VERSION 5.8 ;
BUSBITCHARS "[]" ;
DIVIDERCHAR "/" ;
UNITS
    DATABASE MICRONS 1000 ;
END UNITS

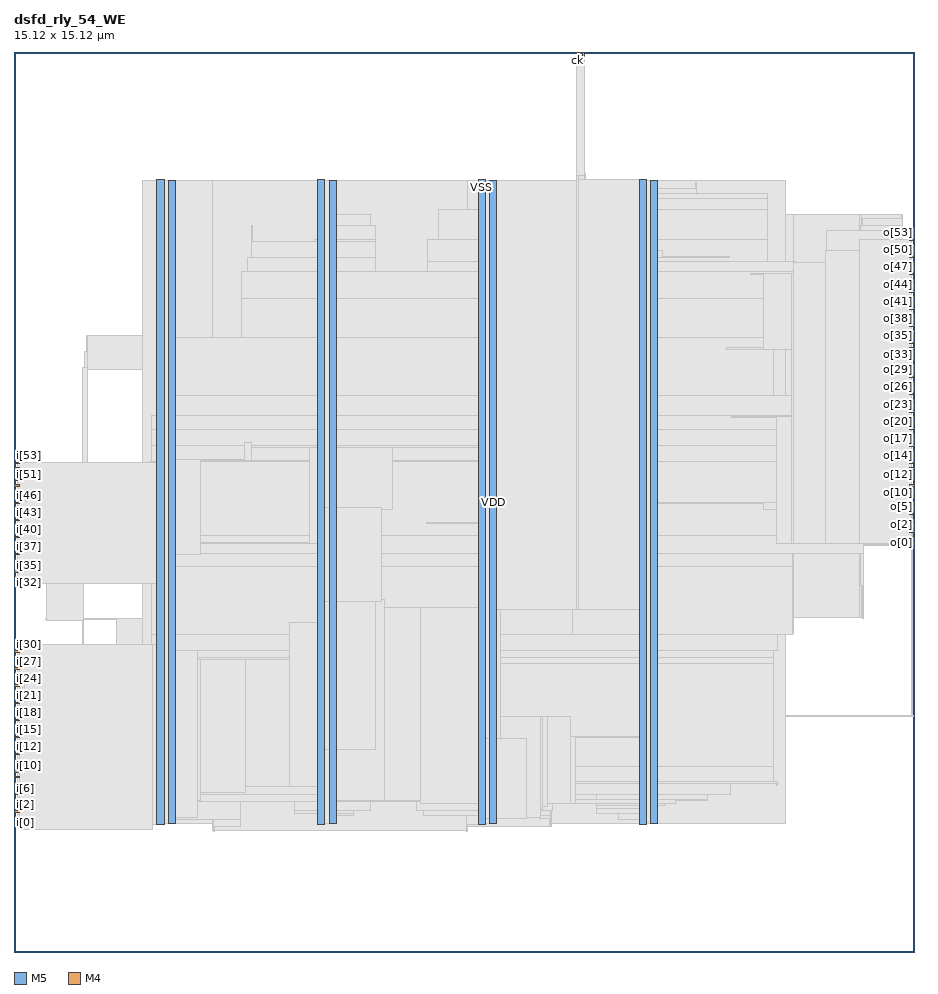
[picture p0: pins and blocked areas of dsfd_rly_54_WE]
MACRO dsfd_rly_54_WE
  FOREIGN dsfd_rly_54_WE 0 0 ;
  CLASS BLOCK ;
  SIZE 15.12 BY 15.12 ;
  PIN ck
    DIRECTION INPUT ;
    USE SIGNAL ;
    PORT
      LAYER M5 ;
        RECT  9.456 15.036 9.48 15.12 ;
    END
  END ck
  PIN i[0]
    DIRECTION INPUT ;
    USE SIGNAL ;
    PORT
      LAYER M4 ;
        RECT  0 2.16 0.084 2.184 ;
    END
  END i[0]
  PIN i[10]
    DIRECTION INPUT ;
    USE SIGNAL ;
    PORT
      LAYER M4 ;
        RECT  0 3.12 0.084 3.144 ;
    END
  END i[10]
  PIN i[11]
    DIRECTION INPUT ;
    USE SIGNAL ;
    PORT
      LAYER M4 ;
        RECT  0 3.216 0.084 3.24 ;
    END
  END i[11]
  PIN i[12]
    DIRECTION INPUT ;
    USE SIGNAL ;
    PORT
      LAYER M4 ;
        RECT  0 3.312 0.084 3.336 ;
    END
  END i[12]
  PIN i[13]
    DIRECTION INPUT ;
    USE SIGNAL ;
    PORT
      LAYER M4 ;
        RECT  0 3.408 0.084 3.432 ;
    END
  END i[13]
  PIN i[14]
    DIRECTION INPUT ;
    USE SIGNAL ;
    PORT
      LAYER M4 ;
        RECT  0 3.504 0.084 3.528 ;
    END
  END i[14]
  PIN i[15]
    DIRECTION INPUT ;
    USE SIGNAL ;
    PORT
      LAYER M4 ;
        RECT  0 3.6 0.084 3.624 ;
    END
  END i[15]
  PIN i[16]
    DIRECTION INPUT ;
    USE SIGNAL ;
    PORT
      LAYER M4 ;
        RECT  0 3.696 0.084 3.72 ;
    END
  END i[16]
  PIN i[17]
    DIRECTION INPUT ;
    USE SIGNAL ;
    PORT
      LAYER M4 ;
        RECT  0 3.792 0.084 3.816 ;
    END
  END i[17]
  PIN i[18]
    DIRECTION INPUT ;
    USE SIGNAL ;
    PORT
      LAYER M4 ;
        RECT  0 3.888 0.084 3.912 ;
    END
  END i[18]
  PIN i[19]
    DIRECTION INPUT ;
    USE SIGNAL ;
    PORT
      LAYER M4 ;
        RECT  0 3.984 0.084 4.008 ;
    END
  END i[19]
  PIN i[1]
    DIRECTION INPUT ;
    USE SIGNAL ;
    PORT
      LAYER M4 ;
        RECT  0 2.256 0.084 2.28 ;
    END
  END i[1]
  PIN i[20]
    DIRECTION INPUT ;
    USE SIGNAL ;
    PORT
      LAYER M4 ;
        RECT  0 4.08 0.084 4.104 ;
    END
  END i[20]
  PIN i[21]
    DIRECTION INPUT ;
    USE SIGNAL ;
    PORT
      LAYER M4 ;
        RECT  0 4.176 0.084 4.2 ;
    END
  END i[21]
  PIN i[22]
    DIRECTION INPUT ;
    USE SIGNAL ;
    PORT
      LAYER M4 ;
        RECT  0 4.272 0.084 4.296 ;
    END
  END i[22]
  PIN i[23]
    DIRECTION INPUT ;
    USE SIGNAL ;
    PORT
      LAYER M4 ;
        RECT  0 4.368 0.084 4.392 ;
    END
  END i[23]
  PIN i[24]
    DIRECTION INPUT ;
    USE SIGNAL ;
    PORT
      LAYER M4 ;
        RECT  0 4.464 0.084 4.488 ;
    END
  END i[24]
  PIN i[25]
    DIRECTION INPUT ;
    USE SIGNAL ;
    PORT
      LAYER M4 ;
        RECT  0 4.56 0.084 4.584 ;
    END
  END i[25]
  PIN i[26]
    DIRECTION INPUT ;
    USE SIGNAL ;
    PORT
      LAYER M4 ;
        RECT  0 4.656 0.084 4.68 ;
    END
  END i[26]
  PIN i[27]
    DIRECTION INPUT ;
    USE SIGNAL ;
    PORT
      LAYER M4 ;
        RECT  0 4.752 0.084 4.776 ;
    END
  END i[27]
  PIN i[28]
    DIRECTION INPUT ;
    USE SIGNAL ;
    PORT
      LAYER M4 ;
        RECT  0 4.848 0.084 4.872 ;
    END
  END i[28]
  PIN i[29]
    DIRECTION INPUT ;
    USE SIGNAL ;
    PORT
      LAYER M4 ;
        RECT  0 4.944 0.084 4.968 ;
    END
  END i[29]
  PIN i[2]
    DIRECTION INPUT ;
    USE SIGNAL ;
    PORT
      LAYER M4 ;
        RECT  0 2.352 0.084 2.376 ;
    END
  END i[2]
  PIN i[30]
    DIRECTION INPUT ;
    USE SIGNAL ;
    PORT
      LAYER M4 ;
        RECT  0 5.04 0.084 5.064 ;
    END
  END i[30]
  PIN i[31]
    DIRECTION INPUT ;
    USE SIGNAL ;
    PORT
      LAYER M4 ;
        RECT  0 5.136 0.084 5.16 ;
    END
  END i[31]
  PIN i[32]
    DIRECTION INPUT ;
    USE SIGNAL ;
    PORT
      LAYER M4 ;
        RECT  0 6.192 0.084 6.216 ;
    END
  END i[32]
  PIN i[33]
    DIRECTION INPUT ;
    USE SIGNAL ;
    PORT
      LAYER M4 ;
        RECT  0 6.288 0.084 6.312 ;
    END
  END i[33]
  PIN i[34]
    DIRECTION INPUT ;
    USE SIGNAL ;
    PORT
      LAYER M4 ;
        RECT  0 6.384 0.084 6.408 ;
    END
  END i[34]
  PIN i[35]
    DIRECTION INPUT ;
    USE SIGNAL ;
    PORT
      LAYER M4 ;
        RECT  0 6.48 0.084 6.504 ;
    END
  END i[35]
  PIN i[36]
    DIRECTION INPUT ;
    USE SIGNAL ;
    PORT
      LAYER M4 ;
        RECT  0 6.576 0.084 6.6 ;
    END
  END i[36]
  PIN i[37]
    DIRECTION INPUT ;
    USE SIGNAL ;
    PORT
      LAYER M4 ;
        RECT  0 6.672 0.084 6.696 ;
    END
  END i[37]
  PIN i[38]
    DIRECTION INPUT ;
    USE SIGNAL ;
    PORT
      LAYER M4 ;
        RECT  0 6.768 0.084 6.792 ;
    END
  END i[38]
  PIN i[39]
    DIRECTION INPUT ;
    USE SIGNAL ;
    PORT
      LAYER M4 ;
        RECT  0 6.864 0.084 6.888 ;
    END
  END i[39]
  PIN i[3]
    DIRECTION INPUT ;
    USE SIGNAL ;
    PORT
      LAYER M4 ;
        RECT  0 2.448 0.084 2.472 ;
    END
  END i[3]
  PIN i[40]
    DIRECTION INPUT ;
    USE SIGNAL ;
    PORT
      LAYER M4 ;
        RECT  0 6.96 0.084 6.984 ;
    END
  END i[40]
  PIN i[41]
    DIRECTION INPUT ;
    USE SIGNAL ;
    PORT
      LAYER M4 ;
        RECT  0 7.056 0.084 7.08 ;
    END
  END i[41]
  PIN i[42]
    DIRECTION INPUT ;
    USE SIGNAL ;
    PORT
      LAYER M4 ;
        RECT  0 7.152 0.084 7.176 ;
    END
  END i[42]
  PIN i[43]
    DIRECTION INPUT ;
    USE SIGNAL ;
    PORT
      LAYER M4 ;
        RECT  0 7.248 0.084 7.272 ;
    END
  END i[43]
  PIN i[44]
    DIRECTION INPUT ;
    USE SIGNAL ;
    PORT
      LAYER M4 ;
        RECT  0 7.344 0.084 7.368 ;
    END
  END i[44]
  PIN i[45]
    DIRECTION INPUT ;
    USE SIGNAL ;
    PORT
      LAYER M4 ;
        RECT  0 7.44 0.084 7.464 ;
    END
  END i[45]
  PIN i[46]
    DIRECTION INPUT ;
    USE SIGNAL ;
    PORT
      LAYER M4 ;
        RECT  0 7.536 0.084 7.56 ;
    END
  END i[46]
  PIN i[47]
    DIRECTION INPUT ;
    USE SIGNAL ;
    PORT
      LAYER M4 ;
        RECT  0 7.632 0.084 7.656 ;
    END
  END i[47]
  PIN i[48]
    DIRECTION INPUT ;
    USE SIGNAL ;
    PORT
      LAYER M4 ;
        RECT  0 7.728 0.084 7.752 ;
    END
  END i[48]
  PIN i[49]
    DIRECTION INPUT ;
    USE SIGNAL ;
    PORT
      LAYER M4 ;
        RECT  0 7.824 0.084 7.848 ;
    END
  END i[49]
  PIN i[4]
    DIRECTION INPUT ;
    USE SIGNAL ;
    PORT
      LAYER M4 ;
        RECT  0 2.544 0.084 2.568 ;
    END
  END i[4]
  PIN i[50]
    DIRECTION INPUT ;
    USE SIGNAL ;
    PORT
      LAYER M4 ;
        RECT  0 7.92 0.084 7.944 ;
    END
  END i[50]
  PIN i[51]
    DIRECTION INPUT ;
    USE SIGNAL ;
    PORT
      LAYER M4 ;
        RECT  0 8.016 0.084 8.04 ;
    END
  END i[51]
  PIN i[52]
    DIRECTION INPUT ;
    USE SIGNAL ;
    PORT
      LAYER M4 ;
        RECT  0 8.112 0.084 8.136 ;
    END
  END i[52]
  PIN i[53]
    DIRECTION INPUT ;
    USE SIGNAL ;
    PORT
      LAYER M4 ;
        RECT  0 8.208 0.084 8.232 ;
    END
  END i[53]
  PIN i[5]
    DIRECTION INPUT ;
    USE SIGNAL ;
    PORT
      LAYER M4 ;
        RECT  0 2.64 0.084 2.664 ;
    END
  END i[5]
  PIN i[6]
    DIRECTION INPUT ;
    USE SIGNAL ;
    PORT
      LAYER M4 ;
        RECT  0 2.736 0.084 2.76 ;
    END
  END i[6]
  PIN i[7]
    DIRECTION INPUT ;
    USE SIGNAL ;
    PORT
      LAYER M4 ;
        RECT  0 2.832 0.084 2.856 ;
    END
  END i[7]
  PIN i[8]
    DIRECTION INPUT ;
    USE SIGNAL ;
    PORT
      LAYER M4 ;
        RECT  0 2.928 0.084 2.952 ;
    END
  END i[8]
  PIN i[9]
    DIRECTION INPUT ;
    USE SIGNAL ;
    PORT
      LAYER M4 ;
        RECT  0 3.024 0.084 3.048 ;
    END
  END i[9]
  PIN o[0]
    DIRECTION OUTPUT ;
    USE SIGNAL ;
    PORT
      LAYER M4 ;
        RECT  15.036 6.864 15.12 6.888 ;
    END
  END o[0]
  PIN o[10]
    DIRECTION OUTPUT ;
    USE SIGNAL ;
    PORT
      LAYER M4 ;
        RECT  15.036 7.824 15.12 7.848 ;
    END
  END o[10]
  PIN o[11]
    DIRECTION OUTPUT ;
    USE SIGNAL ;
    PORT
      LAYER M4 ;
        RECT  15.036 7.92 15.12 7.944 ;
    END
  END o[11]
  PIN o[12]
    DIRECTION OUTPUT ;
    USE SIGNAL ;
    PORT
      LAYER M4 ;
        RECT  15.036 8.016 15.12 8.04 ;
    END
  END o[12]
  PIN o[13]
    DIRECTION OUTPUT ;
    USE SIGNAL ;
    PORT
      LAYER M4 ;
        RECT  15.036 8.112 15.12 8.136 ;
    END
  END o[13]
  PIN o[14]
    DIRECTION OUTPUT ;
    USE SIGNAL ;
    PORT
      LAYER M4 ;
        RECT  15.036 8.208 15.12 8.232 ;
    END
  END o[14]
  PIN o[15]
    DIRECTION OUTPUT ;
    USE SIGNAL ;
    PORT
      LAYER M4 ;
        RECT  15.036 8.304 15.12 8.328 ;
    END
  END o[15]
  PIN o[16]
    DIRECTION OUTPUT ;
    USE SIGNAL ;
    PORT
      LAYER M4 ;
        RECT  15.036 8.4 15.12 8.424 ;
    END
  END o[16]
  PIN o[17]
    DIRECTION OUTPUT ;
    USE SIGNAL ;
    PORT
      LAYER M4 ;
        RECT  15.036 8.496 15.12 8.52 ;
    END
  END o[17]
  PIN o[18]
    DIRECTION OUTPUT ;
    USE SIGNAL ;
    PORT
      LAYER M4 ;
        RECT  15.036 8.592 15.12 8.616 ;
    END
  END o[18]
  PIN o[19]
    DIRECTION OUTPUT ;
    USE SIGNAL ;
    PORT
      LAYER M4 ;
        RECT  15.036 8.688 15.12 8.712 ;
    END
  END o[19]
  PIN o[1]
    DIRECTION OUTPUT ;
    USE SIGNAL ;
    PORT
      LAYER M4 ;
        RECT  15.036 6.96 15.12 6.984 ;
    END
  END o[1]
  PIN o[20]
    DIRECTION OUTPUT ;
    USE SIGNAL ;
    PORT
      LAYER M4 ;
        RECT  15.036 8.784 15.12 8.808 ;
    END
  END o[20]
  PIN o[21]
    DIRECTION OUTPUT ;
    USE SIGNAL ;
    PORT
      LAYER M4 ;
        RECT  15.036 8.88 15.12 8.904 ;
    END
  END o[21]
  PIN o[22]
    DIRECTION OUTPUT ;
    USE SIGNAL ;
    PORT
      LAYER M4 ;
        RECT  15.036 8.976 15.12 9 ;
    END
  END o[22]
  PIN o[23]
    DIRECTION OUTPUT ;
    USE SIGNAL ;
    PORT
      LAYER M4 ;
        RECT  15.036 9.072 15.12 9.096 ;
    END
  END o[23]
  PIN o[24]
    DIRECTION OUTPUT ;
    USE SIGNAL ;
    PORT
      LAYER M4 ;
        RECT  15.036 9.168 15.12 9.192 ;
    END
  END o[24]
  PIN o[25]
    DIRECTION OUTPUT ;
    USE SIGNAL ;
    PORT
      LAYER M4 ;
        RECT  15.036 9.264 15.12 9.288 ;
    END
  END o[25]
  PIN o[26]
    DIRECTION OUTPUT ;
    USE SIGNAL ;
    PORT
      LAYER M4 ;
        RECT  15.036 9.36 15.12 9.384 ;
    END
  END o[26]
  PIN o[27]
    DIRECTION OUTPUT ;
    USE SIGNAL ;
    PORT
      LAYER M4 ;
        RECT  15.036 9.456 15.12 9.48 ;
    END
  END o[27]
  PIN o[28]
    DIRECTION OUTPUT ;
    USE SIGNAL ;
    PORT
      LAYER M4 ;
        RECT  15.036 9.552 15.12 9.576 ;
    END
  END o[28]
  PIN o[29]
    DIRECTION OUTPUT ;
    USE SIGNAL ;
    PORT
      LAYER M4 ;
        RECT  15.036 9.648 15.12 9.672 ;
    END
  END o[29]
  PIN o[2]
    DIRECTION OUTPUT ;
    USE SIGNAL ;
    PORT
      LAYER M4 ;
        RECT  15.036 7.056 15.12 7.08 ;
    END
  END o[2]
  PIN o[30]
    DIRECTION OUTPUT ;
    USE SIGNAL ;
    PORT
      LAYER M4 ;
        RECT  15.036 9.744 15.12 9.768 ;
    END
  END o[30]
  PIN o[31]
    DIRECTION OUTPUT ;
    USE SIGNAL ;
    PORT
      LAYER M4 ;
        RECT  15.036 9.84 15.12 9.864 ;
    END
  END o[31]
  PIN o[32]
    DIRECTION OUTPUT ;
    USE SIGNAL ;
    PORT
      LAYER M4 ;
        RECT  15.036 9.936 15.12 9.96 ;
    END
  END o[32]
  PIN o[33]
    DIRECTION OUTPUT ;
    USE SIGNAL ;
    PORT
      LAYER M4 ;
        RECT  15.036 10.032 15.12 10.056 ;
    END
  END o[33]
  PIN o[34]
    DIRECTION OUTPUT ;
    USE SIGNAL ;
    PORT
      LAYER M4 ;
        RECT  15.036 10.128 15.12 10.152 ;
    END
  END o[34]
  PIN o[35]
    DIRECTION OUTPUT ;
    USE SIGNAL ;
    PORT
      LAYER M4 ;
        RECT  15.036 10.224 15.12 10.248 ;
    END
  END o[35]
  PIN o[36]
    DIRECTION OUTPUT ;
    USE SIGNAL ;
    PORT
      LAYER M4 ;
        RECT  15.036 10.32 15.12 10.344 ;
    END
  END o[36]
  PIN o[37]
    DIRECTION OUTPUT ;
    USE SIGNAL ;
    PORT
      LAYER M4 ;
        RECT  15.036 10.416 15.12 10.44 ;
    END
  END o[37]
  PIN o[38]
    DIRECTION OUTPUT ;
    USE SIGNAL ;
    PORT
      LAYER M4 ;
        RECT  15.036 10.512 15.12 10.536 ;
    END
  END o[38]
  PIN o[39]
    DIRECTION OUTPUT ;
    USE SIGNAL ;
    PORT
      LAYER M4 ;
        RECT  15.036 10.608 15.12 10.632 ;
    END
  END o[39]
  PIN o[3]
    DIRECTION OUTPUT ;
    USE SIGNAL ;
    PORT
      LAYER M4 ;
        RECT  15.036 7.152 15.12 7.176 ;
    END
  END o[3]
  PIN o[40]
    DIRECTION OUTPUT ;
    USE SIGNAL ;
    PORT
      LAYER M4 ;
        RECT  15.036 10.704 15.12 10.728 ;
    END
  END o[40]
  PIN o[41]
    DIRECTION OUTPUT ;
    USE SIGNAL ;
    PORT
      LAYER M4 ;
        RECT  15.036 10.8 15.12 10.824 ;
    END
  END o[41]
  PIN o[42]
    DIRECTION OUTPUT ;
    USE SIGNAL ;
    PORT
      LAYER M4 ;
        RECT  15.036 10.896 15.12 10.92 ;
    END
  END o[42]
  PIN o[43]
    DIRECTION OUTPUT ;
    USE SIGNAL ;
    PORT
      LAYER M4 ;
        RECT  15.036 10.992 15.12 11.016 ;
    END
  END o[43]
  PIN o[44]
    DIRECTION OUTPUT ;
    USE SIGNAL ;
    PORT
      LAYER M4 ;
        RECT  15.036 11.088 15.12 11.112 ;
    END
  END o[44]
  PIN o[45]
    DIRECTION OUTPUT ;
    USE SIGNAL ;
    PORT
      LAYER M4 ;
        RECT  15.036 11.184 15.12 11.208 ;
    END
  END o[45]
  PIN o[46]
    DIRECTION OUTPUT ;
    USE SIGNAL ;
    PORT
      LAYER M4 ;
        RECT  15.036 11.28 15.12 11.304 ;
    END
  END o[46]
  PIN o[47]
    DIRECTION OUTPUT ;
    USE SIGNAL ;
    PORT
      LAYER M4 ;
        RECT  15.036 11.376 15.12 11.4 ;
    END
  END o[47]
  PIN o[48]
    DIRECTION OUTPUT ;
    USE SIGNAL ;
    PORT
      LAYER M4 ;
        RECT  15.036 11.472 15.12 11.496 ;
    END
  END o[48]
  PIN o[49]
    DIRECTION OUTPUT ;
    USE SIGNAL ;
    PORT
      LAYER M4 ;
        RECT  15.036 11.568 15.12 11.592 ;
    END
  END o[49]
  PIN o[4]
    DIRECTION OUTPUT ;
    USE SIGNAL ;
    PORT
      LAYER M4 ;
        RECT  15.036 7.248 15.12 7.272 ;
    END
  END o[4]
  PIN o[50]
    DIRECTION OUTPUT ;
    USE SIGNAL ;
    PORT
      LAYER M4 ;
        RECT  15.036 11.664 15.12 11.688 ;
    END
  END o[50]
  PIN o[51]
    DIRECTION OUTPUT ;
    USE SIGNAL ;
    PORT
      LAYER M4 ;
        RECT  15.036 11.76 15.12 11.784 ;
    END
  END o[51]
  PIN o[52]
    DIRECTION OUTPUT ;
    USE SIGNAL ;
    PORT
      LAYER M4 ;
        RECT  15.036 11.856 15.12 11.88 ;
    END
  END o[52]
  PIN o[53]
    DIRECTION OUTPUT ;
    USE SIGNAL ;
    PORT
      LAYER M4 ;
        RECT  15.036 11.952 15.12 11.976 ;
    END
  END o[53]
  PIN o[5]
    DIRECTION OUTPUT ;
    USE SIGNAL ;
    PORT
      LAYER M4 ;
        RECT  15.036 7.344 15.12 7.368 ;
    END
  END o[5]
  PIN o[6]
    DIRECTION OUTPUT ;
    USE SIGNAL ;
    PORT
      LAYER M4 ;
        RECT  15.036 7.44 15.12 7.464 ;
    END
  END o[6]
  PIN o[7]
    DIRECTION OUTPUT ;
    USE SIGNAL ;
    PORT
      LAYER M4 ;
        RECT  15.036 7.536 15.12 7.56 ;
    END
  END o[7]
  PIN o[8]
    DIRECTION OUTPUT ;
    USE SIGNAL ;
    PORT
      LAYER M4 ;
        RECT  15.036 7.632 15.12 7.656 ;
    END
  END o[8]
  PIN o[9]
    DIRECTION OUTPUT ;
    USE SIGNAL ;
    PORT
      LAYER M4 ;
        RECT  15.036 7.728 15.12 7.752 ;
    END
  END o[9]
  PIN rs
    DIRECTION INPUT ;
    USE SIGNAL ;
    PORT
      LAYER M5 ;
        RECT  9.552 15.036 9.576 15.12 ;
    END
  END rs
  PIN VDD
    DIRECTION INOUT ;
    USE POWER ;
    PORT
      LAYER M5 ;
        RECT  10.692 2.151 10.812 12.969 ;
        RECT  7.992 2.151 8.112 12.969 ;
        RECT  5.292 2.151 5.412 12.969 ;
        RECT  2.592 2.151 2.712 12.969 ;
    END
  END VDD
  PIN VSS
    DIRECTION INOUT ;
    USE GROUND ;
    PORT
      LAYER M5 ;
        RECT  10.5 2.137 10.62 12.983 ;
        RECT  7.8 2.137 7.92 12.983 ;
        RECT  5.1 2.137 5.22 12.983 ;
        RECT  2.4 2.137 2.52 12.983 ;
    END
  END VSS
  # OT_OBS_CLOSED layer=M5 d_um=1.536 added=3
  OBS
    LAYER RVTN ;
     RECT  2.16 2.16 12.96 2.295 ;
     RECT  2.16 2.565 12.96 2.835 ;
     RECT  2.16 3.105 12.96 3.375 ;
     RECT  2.16 3.645 12.96 3.915 ;
     RECT  2.16 4.185 12.96 4.455 ;
     RECT  2.16 4.725 12.96 4.995 ;
     RECT  2.16 5.265 12.96 5.535 ;
     RECT  2.16 5.805 12.96 6.075 ;
     RECT  2.16 6.345 12.96 6.615 ;
     RECT  2.16 6.885 12.96 7.155 ;
     RECT  2.16 7.425 12.96 7.695 ;
     RECT  2.16 7.965 12.96 8.235 ;
     RECT  2.16 8.505 12.96 8.775 ;
     RECT  2.16 9.045 12.96 9.315 ;
     RECT  2.16 9.585 12.96 9.855 ;
     RECT  2.16 10.125 12.96 10.395 ;
     RECT  2.16 10.665 12.96 10.935 ;
     RECT  2.16 11.205 12.96 11.475 ;
     RECT  2.16 11.745 12.96 12.015 ;
     RECT  2.16 12.285 12.96 12.555 ;
     RECT  2.16 12.825 12.96 12.96 ;
    LAYER RVTP ;
     RECT  2.16 2.295 12.96 2.565 ;
     RECT  2.16 2.835 12.96 3.105 ;
     RECT  2.16 3.375 12.96 3.645 ;
     RECT  2.16 3.915 12.96 4.185 ;
     RECT  2.16 4.455 12.96 4.725 ;
     RECT  2.16 4.995 12.96 5.265 ;
     RECT  2.16 5.535 12.96 5.805 ;
     RECT  2.16 6.075 12.96 6.345 ;
     RECT  2.16 6.615 12.96 6.885 ;
     RECT  2.16 7.155 12.96 7.425 ;
     RECT  2.16 7.695 12.96 7.965 ;
     RECT  2.16 8.235 12.96 8.505 ;
     RECT  2.16 8.775 12.96 9.045 ;
     RECT  2.16 9.315 12.96 9.585 ;
     RECT  2.16 9.855 12.96 10.125 ;
     RECT  2.16 10.395 12.96 10.665 ;
     RECT  2.16 10.935 12.96 11.205 ;
     RECT  2.16 11.475 12.96 11.745 ;
     RECT  2.16 12.015 12.96 12.285 ;
     RECT  2.16 12.555 12.96 12.825 ;
    LAYER M1 ;
     RECT  2.16 2.151 12.96 12.969 ;
    LAYER M2 ;
     RECT  0.103 7.704 0.347 7.722 ;
     RECT  0.103 6.822 1.147 6.84 ;
     RECT  1.147 9.792 1.183 9.81 ;
     RECT  1.183 9.792 1.219 10.08 ;
     RECT  1.399 4.734 1.723 4.752 ;
     RECT  0.535 5.58 1.723 5.598 ;
     RECT  0.175 2.268 2.16 2.286 ;
     RECT  1.723 4.734 2.16 5.598 ;
     RECT  1.147 6.822 2.16 7.38 ;
     RECT  1.219 9.792 2.16 10.35 ;
     RECT  2.16 2.151 3.343 12.969 ;
     RECT  3.343 2.034 7.619 12.969 ;
     RECT  7.619 2.106 9.023 12.969 ;
     RECT  9.023 2.151 12.96 12.969 ;
     RECT  12.96 5.346 13.091 12.384 ;
     RECT  13.091 5.616 14.207 12.384 ;
     RECT  14.207 5.616 14.243 6.84 ;
     RECT  14.207 7.776 14.243 12.384 ;
     RECT  14.243 5.616 14.279 5.634 ;
     RECT  14.243 8.784 14.279 10.152 ;
     RECT  14.243 11.016 14.927 12.384 ;
     RECT  14.243 7.776 15.007 7.956 ;
     RECT  14.243 6.822 15.035 6.84 ;
     RECT  15.007 7.632 15.035 7.956 ;
     RECT  14.279 9.396 15.035 9.414 ;
     RECT  14.927 11.016 15.035 11.772 ;
     RECT  12.96 3.96 15.107 3.978 ;
     RECT  15.035 7.632 15.107 7.65 ;
    LAYER M3 ;
     RECT  3.348 2.029 3.366 2.101 ;
     RECT  2.304 2.059 2.322 2.143 ;
     RECT  7.596 2.029 7.614 2.143 ;
     RECT  0.108 2.059 0.126 2.155 ;
     RECT  2.304 2.143 2.505 2.227 ;
     RECT  3.348 2.101 3.798 2.227 ;
     RECT  10.515 2.143 10.605 2.227 ;
     RECT  9 2.101 9.018 2.251 ;
     RECT  0.108 2.155 0.342 2.285 ;
     RECT  5.115 2.143 5.205 2.299 ;
     RECT  7.596 2.143 7.905 2.299 ;
     RECT  8.82 2.251 9.018 2.299 ;
     RECT  5.115 2.299 5.706 2.335 ;
     RECT  10.152 2.227 10.605 2.335 ;
     RECT  4.716 2.335 5.706 2.371 ;
     RECT  6.876 2.299 9.018 2.371 ;
     RECT  9.792 2.335 10.605 2.413 ;
     RECT  9.792 2.413 10.797 2.461 ;
     RECT  9.792 2.461 10.926 2.491 ;
     RECT  2.304 2.227 3.798 2.533 ;
     RECT  4.716 2.371 5.994 2.533 ;
     RECT  6.768 2.371 9.054 2.533 ;
     RECT  9.792 2.491 11.106 2.539 ;
     RECT  2.304 2.533 9.054 2.641 ;
     RECT  9.792 2.539 11.646 2.641 ;
     RECT  2.304 2.641 12.042 2.839 ;
     RECT  12.816 2.803 12.834 2.839 ;
     RECT  2.304 2.839 12.834 2.867 ;
     RECT  1.404 2.731 1.422 3.115 ;
     RECT  2.304 2.867 12.762 3.115 ;
     RECT  0.18 2.285 0.342 3.163 ;
     RECT  0.144 3.163 0.342 3.341 ;
     RECT  0.324 4.363 0.342 4.493 ;
     RECT  1.404 3.115 12.762 4.843 ;
     RECT  1.152 4.843 12.762 4.955 ;
     RECT  2.304 4.955 12.762 5.071 ;
     RECT  2.304 5.071 12.834 5.341 ;
     RECT  1.152 4.955 1.17 5.575 ;
     RECT  14.256 5.611 14.274 6.151 ;
     RECT  0.54 5.575 1.17 6.413 ;
     RECT  2.304 5.341 13.086 6.475 ;
     RECT  2.268 6.475 13.086 6.691 ;
     RECT  14.22 6.151 14.274 6.691 ;
     RECT  15.084 3.955 15.102 6.817 ;
     RECT  0.108 6.817 0.126 6.893 ;
     RECT  2.268 6.691 14.274 6.989 ;
     RECT  13.644 6.989 14.274 7.259 ;
     RECT  0.324 7.531 0.342 7.627 ;
     RECT  15.012 6.817 15.102 7.655 ;
     RECT  0.108 7.627 0.342 7.727 ;
     RECT  0.324 7.727 0.342 7.757 ;
     RECT  13.68 7.259 14.274 7.771 ;
     RECT  15.012 7.655 15.03 7.771 ;
     RECT  1.152 6.413 1.17 7.819 ;
     RECT  13.68 7.771 15.03 7.853 ;
     RECT  13.68 7.853 14.238 7.949 ;
     RECT  1.152 7.819 1.206 8.107 ;
     RECT  14.976 7.853 15.03 8.141 ;
     RECT  2.268 6.989 12.834 8.237 ;
     RECT  14.976 8.141 14.994 8.429 ;
     RECT  2.304 8.237 12.834 8.509 ;
     RECT  2.304 8.509 13.122 8.779 ;
     RECT  14.148 7.949 14.238 8.779 ;
     RECT  2.304 8.779 14.274 9.005 ;
     RECT  2.415 9.005 14.274 9.347 ;
     RECT  15.012 9.355 15.03 9.419 ;
     RECT  1.152 8.107 1.242 9.815 ;
     RECT  1.188 9.815 1.242 10.085 ;
     RECT  13.608 9.347 14.274 10.253 ;
     RECT  2.415 9.347 12.762 10.319 ;
     RECT  1.224 10.085 1.242 10.355 ;
     RECT  13.608 10.253 14.238 10.541 ;
     RECT  14.076 10.541 14.238 10.829 ;
     RECT  3.816 10.319 12.762 10.987 ;
     RECT  15.012 10.699 15.03 11.179 ;
     RECT  14.112 10.829 14.238 11.275 ;
     RECT  14.976 11.179 15.03 11.275 ;
     RECT  3.816 10.987 13.122 11.435 ;
     RECT  6.948 11.435 13.122 11.597 ;
     RECT  3.924 11.435 6.066 11.669 ;
     RECT  14.112 11.275 15.03 11.755 ;
     RECT  13.644 11.755 15.03 11.777 ;
     RECT  3.996 11.669 6.066 11.939 ;
     RECT  5.04 11.939 6.066 11.975 ;
     RECT  6.948 11.597 12.654 11.975 ;
     RECT  13.644 11.777 14.922 12.119 ;
     RECT  3.996 11.939 4.014 12.209 ;
     RECT  5.115 11.975 6.066 12.209 ;
     RECT  14.22 12.119 14.922 12.209 ;
     RECT  14.256 12.209 14.922 12.317 ;
     RECT  5.115 12.209 5.994 12.389 ;
     RECT  14.904 12.317 14.922 12.389 ;
     RECT  7.128 11.975 12.654 12.479 ;
     RECT  7.815 12.479 12.654 12.659 ;
     RECT  2.415 10.319 2.697 12.707 ;
     RECT  5.115 12.389 5.397 12.707 ;
     RECT  7.815 12.659 8.097 12.707 ;
     RECT  9.216 12.659 12.654 12.749 ;
     RECT  9.216 12.749 11.466 12.821 ;
     RECT  9.216 12.821 10.605 12.893 ;
     RECT  9.216 12.893 9.594 12.929 ;
     RECT  11.448 12.821 11.466 12.929 ;
     RECT  2.415 12.707 2.505 12.977 ;
     RECT  5.115 12.707 5.205 12.977 ;
     RECT  7.815 12.707 7.905 12.977 ;
     RECT  10.515 12.893 10.605 12.977 ;
     RECT  9.576 12.929 9.594 13.085 ;
    LAYER M4 ;
     RECT  0.06 2.16 0.097 5.16 ;
     RECT  0.097 2.064 2.333 5.16 ;
     RECT  2.333 2.148 2.408 5.16 ;
     RECT  0.06 6.192 2.408 8.232 ;
     RECT  2.408 2.148 2.512 12.972 ;
     RECT  2.512 2.256 2.704 12.702 ;
     RECT  2.704 2.256 3.089 5.064 ;
     RECT  3.089 2.544 3.125 4.92 ;
     RECT  2.704 6.672 3.125 8.28 ;
     RECT  3.125 8.256 3.877 8.28 ;
     RECT  3.125 2.688 3.881 4.92 ;
     RECT  3.877 8.256 3.989 8.568 ;
     RECT  3.881 2.784 4.633 4.92 ;
     RECT  3.125 6.864 4.957 6.888 ;
     RECT  3.989 8.256 4.957 8.472 ;
     RECT  4.633 2.784 5.108 5.544 ;
     RECT  4.957 6.864 5.108 8.472 ;
     RECT  5.108 2.148 5.212 12.972 ;
     RECT  5.212 2.418 5.404 12.702 ;
     RECT  5.404 2.544 6.22 5.928 ;
     RECT  5.404 7.44 6.365 8.472 ;
     RECT  6.22 2.544 6.829 5.784 ;
     RECT  6.829 2.496 7.808 5.784 ;
     RECT  6.937 7.2 7.808 7.224 ;
     RECT  6.365 8.256 7.808 8.472 ;
     RECT  7.808 2.148 7.912 12.972 ;
     RECT  7.912 2.256 8.104 12.702 ;
     RECT  8.104 2.256 8.165 5.784 ;
     RECT  8.104 7.2 8.345 7.224 ;
     RECT  8.165 2.256 8.849 3.96 ;
     RECT  8.849 2.4 8.885 3.96 ;
     RECT  8.885 2.448 8.957 3.96 ;
     RECT  8.957 2.496 9.353 3.96 ;
     RECT  8.165 5.328 9.389 5.784 ;
     RECT  9.353 2.496 9.425 3.624 ;
     RECT  9.389 5.76 9.491 5.784 ;
     RECT  9.521 13.056 9.605 13.08 ;
     RECT  9.425 2.496 10.508 2.568 ;
     RECT  9.425 3.6 10.508 3.624 ;
     RECT  9.133 7.392 10.508 7.416 ;
     RECT  9.925 11.76 10.508 11.784 ;
     RECT  10.508 2.148 10.612 12.972 ;
     RECT  10.612 2.418 10.804 12.702 ;
     RECT  10.804 11.664 10.901 11.784 ;
     RECT  10.804 2.496 11.117 2.568 ;
     RECT  11.117 2.544 11.657 2.568 ;
     RECT  10.901 11.664 12.017 11.688 ;
     RECT  10.804 7.536 12.589 7.56 ;
     RECT  11.977 10.128 12.589 10.152 ;
     RECT  12.373 11.376 12.589 11.4 ;
     RECT  12.589 7.44 12.805 7.56 ;
     RECT  12.049 8.976 12.805 9 ;
     RECT  12.805 6.864 13.057 9 ;
     RECT  12.589 10.128 13.057 11.4 ;
     RECT  13.057 6.864 13.093 11.4 ;
     RECT  13.093 6.864 13.633 11.592 ;
     RECT  13.633 6.864 14.209 11.784 ;
     RECT  14.209 6.864 15.084 11.976 ;
    LAYER M5 ;
     RECT  2.4 2.137 2.52 2.151 ;
     RECT  5.1 2.137 5.22 2.151 ;
     RECT  7.8 2.137 7.92 2.151 ;
     RECT  10.5 2.137 10.62 2.151 ;
     RECT  7.8 2.151 8.112 2.245 ;
     RECT  0.192 2.389 0.216 2.579 ;
     RECT  5.1 2.151 5.412 3.397 ;
     RECT  7.8 2.245 8.616 3.587 ;
     RECT  0.144 4.213 0.168 4.499 ;
     RECT  5.1 3.397 6.072 5.893 ;
     RECT  5.1 5.893 6.168 7.475 ;
     RECT  0.192 7.573 0.216 7.763 ;
     RECT  2.4 2.151 2.712 12.969 ;
     RECT  5.1 7.475 5.412 12.969 ;
     RECT  7.8 3.587 8.112 12.969 ;
     RECT  10.5 2.151 10.812 12.969 ;
     RECT  2.4 12.969 2.52 12.983 ;
     RECT  5.1 12.969 5.22 12.983 ;
     RECT  7.8 12.969 7.92 12.983 ;
     RECT  10.5 12.969 10.62 12.983 ;
     RECT  9.456 5.749 9.48 13.045 ;
     RECT  9.456 13.045 9.576 15.056 ;
     RECT  8.112 5.749 9.456 12.969 ;
     RECT  9.48 5.749 10.5 12.983 ;
     RECT  9.48 12.983 9.576 13.045 ;
  END
END dsfd_rly_54_WE
END LIBRARY
